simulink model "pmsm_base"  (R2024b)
settings: Solver=ode4  StartTime=0.0  StopTime=1  FixedStep=1e-6  RelTol=1e-3
undefined symbols (not defined in the file or in its folder): by, DiscIntNeverNeededParam, established, Flux, linkage, magnets, V
libraries: spsDCVoltageSourceLib x1, spsPermanentMagnetSynchronousMachineLib x1, simulink x1, spsTwoLevelConverterLib x1, sps_lib x1

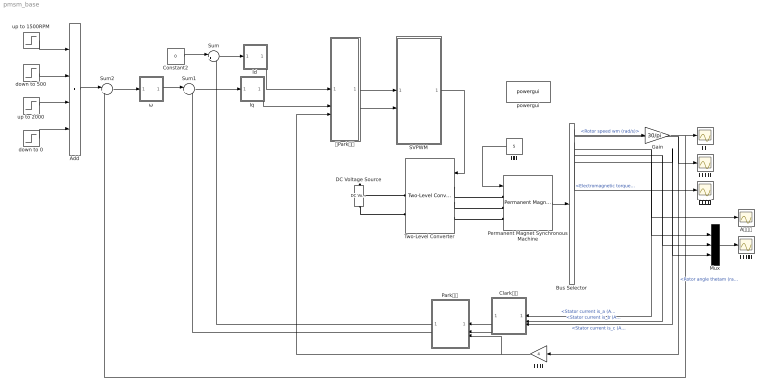
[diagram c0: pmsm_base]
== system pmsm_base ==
  Add : Sum  Inputs=++++
  A相电流 : Scope
  Bus Selector : BusSelector  OutputSignals=Rotor speed wm (rad/s),Rotor angle thetam (rad),Electromagnetic torque Te (N*m),Stator current is_a (A),Stator current is_b (A),Stator current is_c (A)
  Clark变换 : Subsystem
  Constant2 : Constant  Value=0
  DC Voltage Source : spsDCVoltageSourceLib/DC Voltage Source  Amplitude=560  Measurements=None
  Gain : Gain  Gain=30/pi
  Id : Subsystem  mask{Kp=9, Ki=800, Par_limits=[323 -323], Init=0, Ts=1e-6, Kb=89}
      mask prompts: Kp "Proportional gain(Kp):"; Ki "Integral gain(Ki):"; Par_limits "Output limits:[Upper Lower]"; Init "Output Init value:"; Ts "Sample time:"; Kb "Anti-windup gain Kb (1/s)"
      mask init:
      | Upperlimit = Par_limits(1);
      | Lowerlimit = Par_limits(2);
  Iq : Subsystem  mask{Kp=12, Ki=3000, Par_limits=[323 -323], Init=0, Ts=1e-6, Kb=250}
      mask prompts: Kp "Proportional gain(Kp):"; Ki "Integral gain(Ki):"; Par_limits "Output limits:[Upper Lower]"; Init "Output Init value:"; Ts "Sample time:"; Kb "Anti-windup gain Kb (1/s)"
      mask init:
      | Upperlimit = Par_limits(1);
      | Lowerlimit = Par_limits(2);
  Mux : Mux  Inputs=3
  Park变换 : Subsystem
  Permanent Magnet Synchronous Machine : spsPermanentMagnetSynchronousMachineLib/Permanent Magnet Synchronous Machine  NbPhases=3  FluxDistribution=Sinusoidal  RotorType=Round  MechanicalLoad=Torque Tm  PresetModel="11:  26.13 Nm 560 Vdc 3000 RPM - 27.3 Nm"  ShowDetailedParameters=on  MeasurementBus=off  Resistance=0.11  Inductance=8.5e-3  dqInductances=[8.5e-3,8.5e-3]  La=0.00097  MachineConstant=Flux linkage established by magnets (V.s)  Flux=0.1119  VoltageCst=81.1857  TorqueCst=0.6714  Flat=120  Mechanical=[0.0016 0.0002024 4 0]  PolePairs=4  InitialConditions=[0,0, 0,0]  InitialConditions5ph=[0 0 0 0 0 0]  RefAngle=Aligned with phase A axis (original Park)  IterativeDiscreteModel=Trapezoidal non iterative  TsBlock=-1  TsPowergui=0
  SVPWM : Subsystem
  Sum : Sum  Inputs=|+-
  Sum1 : Sum  Inputs=|+-
  Sum2 : Sum  Inputs=|+-
  Two-Level Converter : spsTwoLevelConverterLib/Two-Level Converter  ModelType=Switching devices  Ron=1e-3  Rs=1e6  Cs=inf  Vforward=[0,0]  Ron_Diode=1e-3  Rs_Diode=1e6  Cs_Diode=inf  Vf_Diode=1e-3  Rs_CurrentSource=inf  Ron_ACsource=1e-3
  down to 0 : Step  Time=0.8  After=-2000  SampleTime=0
  down to 500 : Step  Time=0.4  After=-1000  SampleTime=0
  powergui : sps_lib/powergui  Priority=1  SimulationMode=Discrete  SampleTime=1e-6  frequency=60  Iterations=50  frequencyindice=0  Pbase=100e6  ErrMax=1e-4  UnitsV=kV  UnitsW=MW  buscounter=0  FunctionMessages=off  echomessages=off  EnableUseOfTLC=off  CurrentSourceSwitches=off  DisableSnubberDevices=off  DisableRonSwitches=off  DisableVfSwitches=off  DisplayEquations=off  AutomaticDiscreteSolvers=off  SolverType=Tustin/Backward Euler (TBE)  Interpol=off  ExternalGateDelay=off  methode=off  Ts=100  x0status=blocks  SPID=on  SwTol=0  HookPort=off  NonlinearTolerance=1e-4  nMaxIteration=100  ContinueOnMaxIteration=off  RestoreLinks=warning  ResistiveCurrentMeasurement=off  Frange=[0:2:500]  Ylog=off  Xlog=on  ShowGrid=off  save=off  variable=ZData  structure=0  ZoomFFT=off  StartTime=0.0  cycles=1  DisplayStyle=1  fundamental=60  FreqAxis=off  MaxFrequency=1000  frequencyindicesteady=1  RmsSteady=1  display=off
  up to 1500RPM : Step  Time=0.1  After=1500  SampleTime=0
  up to 2000 : Step  Time=0.6  After=1500  SampleTime=0
  ω : Subsystem  mask{Kp=1.2, Ki=1000, Par_limits=[30 -30], Init=0, Ts=1e-6, Kb=1600}
      mask prompts: Kp "Proportional gain(Kp):"; Ki "Integral gain(Ki):"; Par_limits "Output limits:[Upper Lower]"; Init "Output Init value:"; Ts "Sample time:"; Kb "Anti-windup gain Kb (1/s)"
      mask init:
      | Upperlimit = Par_limits(1);
      | Lowerlimit = Par_limits(2);
  反Park变换 : Subsystem
  定子电流 : Scope
  机械角度 : Scope
  极对数 : Gain  Gain=4
  电磁转矩 : Scope
  负载 : Constant  Value=5
  转速 : Scope
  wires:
  Constant2/1 -> Sum/1
  极对数/1 -> Park变换/3(angle), 反Park变换/3(angle)
  Sum1/1 -> Iq/1(Err)
  Park变换/1(D) -> Sum/2
  ω/1(Out) -> Sum1/1
  Sum2/1 -> ω/1(Err)
  Bus Selector/5 -> Mux/2, Clark变换/2(b)  "<Stator current is_b (A)>"
  Bus Selector/6 -> Mux/3, Clark变换/3(c)  "<Stator current is_c (A)>"
  Bus Selector/4 -> A相电流/1, Clark变换/1(a), Mux/1  "<Stator current is_a (A)>"
  Gain/1 -> Sum2/2, 转速/1
  Bus Selector/1 -> Gain/1  "<Rotor speed wm (rad/s)>"
  Iq/1(Out) -> 反Park变换/2(Q)
  Park变换/2(Q) -> Sum1/2
  Bus Selector/3 -> 电磁转矩/1  "<Electromagnetic torque Te (N*m)>"
  Permanent Magnet Synchronous Machine/1 -> Bus Selector/1
  Bus Selector/2 -> 极对数/1, 机械角度/1  "<Rotor angle thetam (rad)>"
  SVPWM/1(PWM) -> Two-Level Converter/1
  反Park变换/1(alpha) -> SVPWM/1(alpha)
  反Park变换/2(beta) -> SVPWM/2(beta)
  Clark变换/1(alpha) -> Park变换/1(alpha)
  Clark变换/2(beta) -> Park变换/2(beta)
  Mux/1 -> 定子电流/1
  负载/1 -> Permanent Magnet Synchronous Machine/1
  Sum/1 -> Id/1(Err)
  Id/1(Out) -> 反Park变换/1(D)
  up to 2000/1 -> Add/3
  down to 0/1 -> Add/4
  down to 500/1 -> Add/2
  up to 1500RPM/1 -> Add/1
  Add/1 -> Sum2/1
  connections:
  DC Voltage Source/LConn1 -- Two-Level Converter/RConn2
  Two-Level Converter/LConn2 -- Permanent Magnet Synchronous Machine/LConn2
  DC Voltage Source/RConn1 -- Two-Level Converter/RConn1
  Two-Level Converter/LConn1 -- Permanent Magnet Synchronous Machine/LConn1
  Two-Level Converter/LConn3 -- Permanent Magnet Synchronous Machine/LConn3

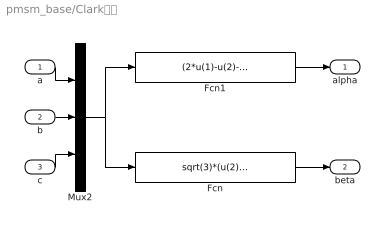
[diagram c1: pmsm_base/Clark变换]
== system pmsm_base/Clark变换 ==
  a : Inport
  b : Inport  Port=2
  c : Inport  Port=3
  Fcn : Fcn  Expr=sqrt(3)*(u(2)-u(3))/3
  Fcn1 : Fcn  Expr=(2*u(1)-u(2)-u(3))/3
  Mux2 : Mux  Inputs=3
  alpha : Outport
  beta : Outport  Port=2
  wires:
  Mux2/1 -> Fcn1/1, Fcn/1
  a/1 -> Mux2/1
  c/1 -> Mux2/3
  b/1 -> Mux2/2
  Fcn1/1 -> alpha/1
  Fcn/1 -> beta/1

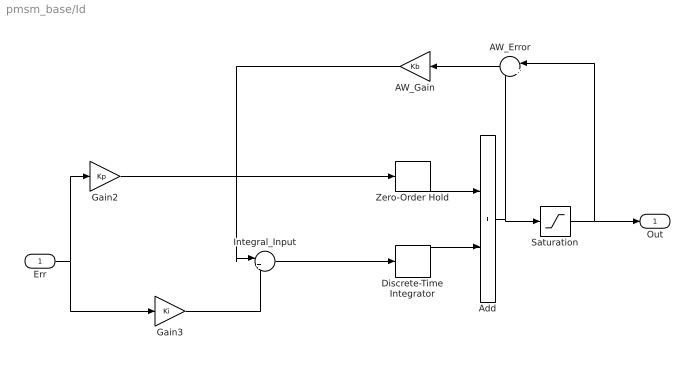
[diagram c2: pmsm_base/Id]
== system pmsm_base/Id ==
  Err : Inport
  AW_Error : Sum  Inputs=|+-
  AW_Gain : Gain  Gain=Kb
  Add : Sum
  Discrete-Time Integrator : DiscreteIntegrator  InitialCondition=Init  SampleTime=Ts  LimitOutput=on  UpperSaturationLimit=160  LowerSaturationLimit=-160  ICPrevOutput=DiscIntNeverNeededParam  ICPrevScaledInput=DiscIntNeverNeededParam
  Gain2 : Gain  Gain=Kp
  Gain3 : Gain  Gain=Ki
  Integral_Input : Sum  Inputs=|++
  Saturation : Saturate  UpperLimit=Upperlimit  LowerLimit=Lowerlimit
  Zero-Order Hold : ZeroOrderHold  SampleTime=Ts
  Out : Outport
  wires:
  Discrete-Time Integrator/1 -> Add/2
  Zero-Order Hold/1 -> Add/1
  Saturation/1 -> AW_Error/1, Out/1
  Add/1 -> AW_Error/2, Saturation/1
  Gain2/1 -> Zero-Order Hold/1
  Err/1 -> Gain2/1, Gain3/1
  AW_Error/1 -> AW_Gain/1
  AW_Gain/1 -> Integral_Input/1
  Gain3/1 -> Integral_Input/2
  Integral_Input/1 -> Discrete-Time Integrator/1

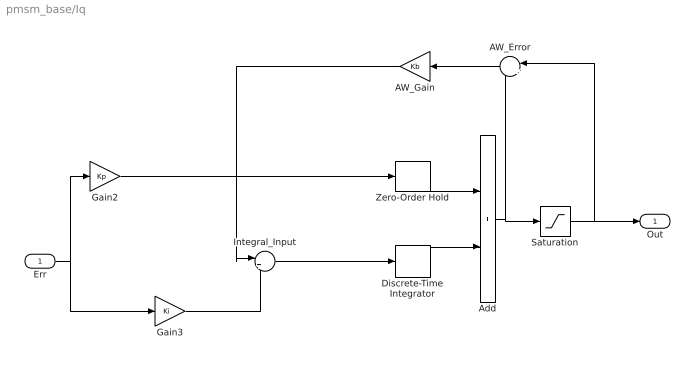
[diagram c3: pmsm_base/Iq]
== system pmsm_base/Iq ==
  Err : Inport
  AW_Error : Sum  Inputs=|+-
  AW_Gain : Gain  Gain=Kb
  Add : Sum
  Discrete-Time Integrator : DiscreteIntegrator  InitialCondition=Init  SampleTime=Ts  LimitOutput=on  UpperSaturationLimit=160  LowerSaturationLimit=-160  ICPrevOutput=DiscIntNeverNeededParam  ICPrevScaledInput=DiscIntNeverNeededParam
  Gain2 : Gain  Gain=Kp
  Gain3 : Gain  Gain=Ki
  Integral_Input : Sum  Inputs=|++
  Saturation : Saturate  UpperLimit=Upperlimit  LowerLimit=Lowerlimit
  Zero-Order Hold : ZeroOrderHold  SampleTime=Ts
  Out : Outport
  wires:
  Integral_Input/1 -> Discrete-Time Integrator/1
  Gain3/1 -> Integral_Input/2
  AW_Gain/1 -> Integral_Input/1
  AW_Error/1 -> AW_Gain/1
  Err/1 -> Gain3/1, Gain2/1
  Gain2/1 -> Zero-Order Hold/1
  Add/1 -> Saturation/1, AW_Error/2
  Saturation/1 -> Out/1, AW_Error/1
  Zero-Order Hold/1 -> Add/1
  Discrete-Time Integrator/1 -> Add/2

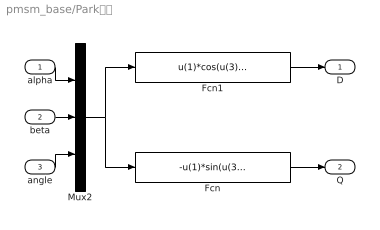
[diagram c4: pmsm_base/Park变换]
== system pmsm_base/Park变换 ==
  alpha : Inport
  beta : Inport  Port=2
  angle : Inport  Port=3
  Fcn : Fcn  Expr=-u(1)*sin(u(3))+u(2)*cos(u(3))
  Fcn1 : Fcn  Expr=u(1)*cos(u(3))+u(2)*sin(u(3))
  Mux2 : Mux  Inputs=3
  D : Outport
  Q : Outport  Port=2
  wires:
  Mux2/1 -> Fcn1/1, Fcn/1
  alpha/1 -> Mux2/1
  angle/1 -> Mux2/3
  beta/1 -> Mux2/2
  Fcn1/1 -> D/1
  Fcn/1 -> Q/1

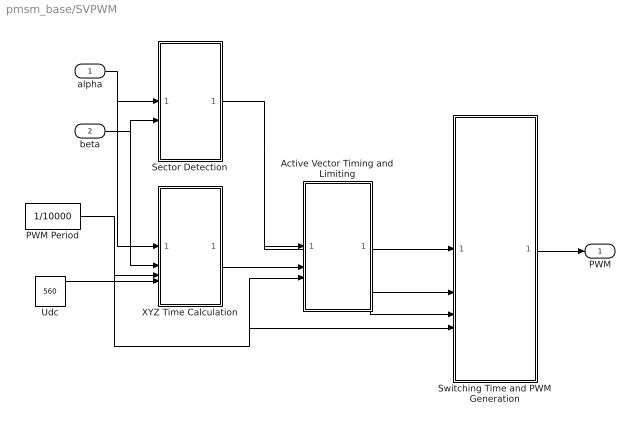
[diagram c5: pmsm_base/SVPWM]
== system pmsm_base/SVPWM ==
  alpha : Inport
  beta : Inport  Port=2
  Active Vector Timing and Limiting : Subsystem
  PWM Period : Constant  Value=1/10000
  Sector Detection : Subsystem
  Switching Time and PWM Generation : Subsystem
  Udc : Constant  Value=560
  XYZ Time Calculation : Subsystem
  PWM : Outport
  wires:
  alpha/1 -> XYZ Time Calculation/1(alpha), Sector Detection/1(alpha)
  beta/1 -> XYZ Time Calculation/2(beta), Sector Detection/2(beta)
  Sector Detection/1(N) -> Switching Time and PWM Generation/1(N), Active Vector Timing and Limiting/1(N)
  PWM Period/1 -> XYZ Time Calculation/3(Ts), Switching Time and PWM Generation/4(Ts), Active Vector Timing and Limiting/3(Ts)
  Active Vector Timing and Limiting/1(T1) -> Switching Time and PWM Generation/2(T1)
  Active Vector Timing and Limiting/2(T2) -> Switching Time and PWM Generation/3(T2)
  XYZ Time Calculation/1(XYZ) -> Active Vector Timing and Limiting/2(XYZ)
  Udc/1 -> XYZ Time Calculation/4(Udc)
  Switching Time and PWM Generation/1(PWM) -> PWM/1

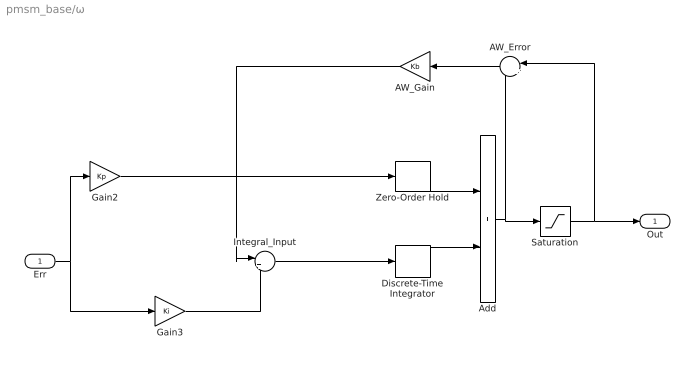
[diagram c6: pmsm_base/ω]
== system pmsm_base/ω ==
  Err : Inport
  AW_Error : Sum  Inputs=|+-
  AW_Gain : Gain  Gain=Kb
  Add : Sum
  Discrete-Time Integrator : DiscreteIntegrator  InitialCondition=Init  SampleTime=Ts  LimitOutput=on  UpperSaturationLimit=23  LowerSaturationLimit=-23  ICPrevOutput=DiscIntNeverNeededParam  ICPrevScaledInput=DiscIntNeverNeededParam
  Gain2 : Gain  Gain=Kp
  Gain3 : Gain  Gain=Ki
  Integral_Input : Sum  Inputs=|++
  Saturation : Saturate  UpperLimit=Upperlimit  LowerLimit=Lowerlimit
  Zero-Order Hold : ZeroOrderHold  SampleTime=Ts
  Out : Outport
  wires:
  Discrete-Time Integrator/1 -> Add/2
  Zero-Order Hold/1 -> Add/1
  Saturation/1 -> AW_Error/1, Out/1
  Add/1 -> AW_Error/2, Saturation/1
  Gain2/1 -> Zero-Order Hold/1
  Err/1 -> Gain2/1, Gain3/1
  AW_Error/1 -> AW_Gain/1
  AW_Gain/1 -> Integral_Input/1
  Gain3/1 -> Integral_Input/2
  Integral_Input/1 -> Discrete-Time Integrator/1

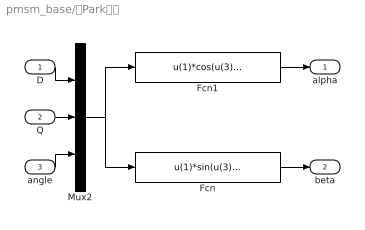
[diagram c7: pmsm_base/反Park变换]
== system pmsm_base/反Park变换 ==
  D : Inport
  Q : Inport  Port=2
  angle : Inport  Port=3
  Fcn : Fcn  Expr=u(1)*sin(u(3))+u(2)*cos(u(3))
  Fcn1 : Fcn  Expr=u(1)*cos(u(3))-u(2)*sin(u(3))
  Mux2 : Mux  Inputs=3
  alpha : Outport
  beta : Outport  Port=2
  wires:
  Mux2/1 -> Fcn1/1, Fcn/1
  D/1 -> Mux2/1
  angle/1 -> Mux2/3
  Q/1 -> Mux2/2
  Fcn1/1 -> alpha/1
  Fcn/1 -> beta/1

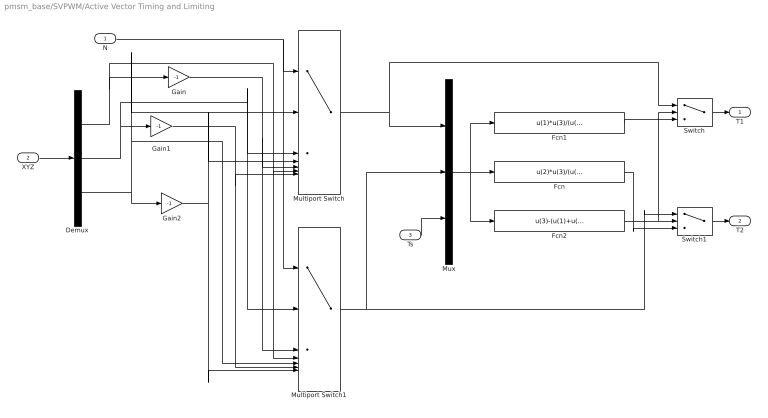
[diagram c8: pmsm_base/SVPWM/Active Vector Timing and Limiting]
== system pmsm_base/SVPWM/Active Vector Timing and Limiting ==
  N : Inport
  XYZ : Inport  Port=2
  Ts : Inport  Port=3
  Demux : Demux  Outputs=3
  Fcn : Fcn  Expr=u(2)*u(3)/(u(1)+u(2))
  Fcn1 : Fcn  Expr=u(1)*u(3)/(u(1)+u(2))
  Fcn2 : Fcn  Expr=u(3)-(u(1)+u(2))
  Gain : Gain  Gain=-1
  Gain1 : Gain  Gain=-1
  Gain2 : Gain  Gain=-1
  Multiport Switch : MultiPortSwitch  Inputs=6
  Multiport Switch1 : MultiPortSwitch  Inputs=6
  Mux : Mux  Inputs=3
  Switch : Switch  Criteria=u2 > Threshold
  Switch1 : Switch  Criteria=u2 > Threshold
  T1 : Outport
  T2 : Outport  Port=2
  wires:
  XYZ/1 -> Demux/1
  N/1 -> Multiport Switch/1, Multiport Switch1/1
  Demux/1 -> Multiport Switch/6, Multiport Switch1/4, Gain/1
  Gain/1 -> Multiport Switch1/3, Multiport Switch/5
  Demux/2 -> Multiport Switch/3, Multiport Switch1/2, Gain1/1
  Gain1/1 -> Multiport Switch1/6, Multiport Switch/7
  Demux/3 -> Multiport Switch1/5, Multiport Switch/2, Gain2/1
  Gain2/1 -> Multiport Switch1/7, Multiport Switch/4
  Multiport Switch/1 -> Mux/1, Switch/1
  Multiport Switch1/1 -> Mux/2, Switch1/1
  Ts/1 -> Mux/3
  Mux/1 -> Fcn/1, Fcn2/1, Fcn1/1
  Fcn2/1 -> Switch/2, Switch1/2
  Fcn1/1 -> Switch/3
  Fcn/1 -> Switch1/3
  Switch/1 -> T1/1
  Switch1/1 -> T2/1

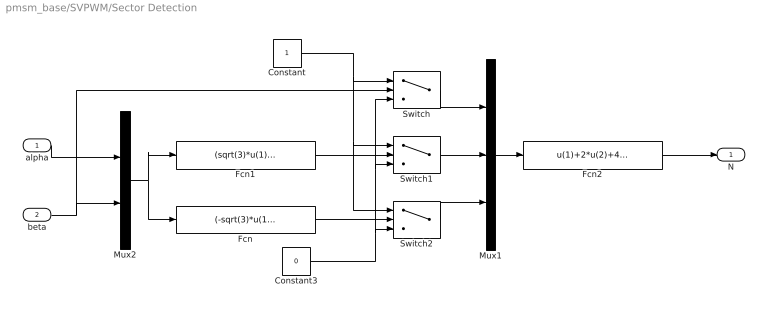
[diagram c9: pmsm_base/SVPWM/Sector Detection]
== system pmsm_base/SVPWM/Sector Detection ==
  alpha : Inport
  beta : Inport  Port=2
  Constant : Constant
  Constant3 : Constant  Value=0
  Fcn : Fcn  Expr=(-sqrt(3)*u(1)-u(2))/2
  Fcn1 : Fcn  Expr=(sqrt(3)*u(1)-u(2))/2
  Fcn2 : Fcn  Expr=u(1)+2*u(2)+4*u(3)
  Mux1 : Mux  Inputs=3
  Mux2 : Mux  Inputs=2
  Switch : Switch  Criteria=u2 > Threshold
  Switch1 : Switch  Criteria=u2 > Threshold
  Switch2 : Switch  Criteria=u2 > Threshold
  N : Outport
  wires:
  Constant3/1 -> Switch/3, Switch1/3, Switch2/3
  Switch/1 -> Mux1/1
  Mux2/1 -> Fcn/1, Fcn1/1
  Mux1/1 -> Fcn2/1
  Fcn1/1 -> Switch1/2
  Constant/1 -> Switch/1, Switch1/1, Switch2/1
  Switch2/1 -> Mux1/3
  Fcn/1 -> Switch2/2
  Switch1/1 -> Mux1/2
  beta/1 -> Switch/2, Mux2/2
  alpha/1 -> Mux2/1
  Fcn2/1 -> N/1

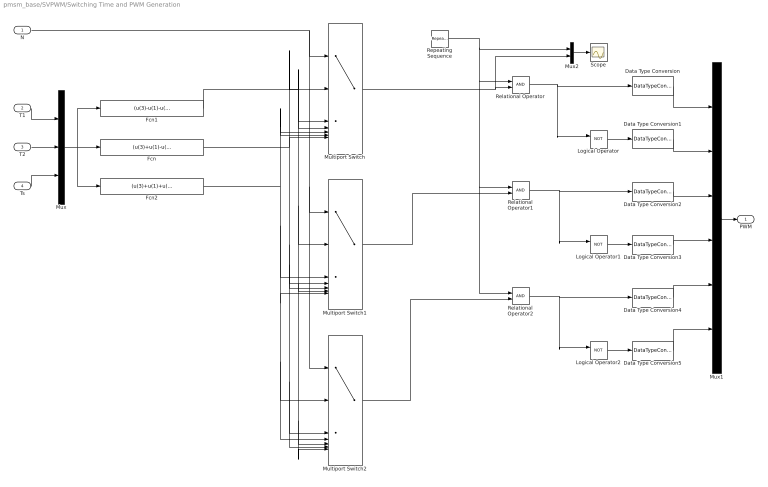
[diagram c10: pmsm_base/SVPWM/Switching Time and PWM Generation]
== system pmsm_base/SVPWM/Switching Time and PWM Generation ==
  N : Inport
  T1 : Inport  Port=2
  T2 : Inport  Port=3
  Ts : Inport  Port=4
  Data Type Conversion{,1..5} (6 alike) : DataTypeConversion  OutDataTypeStr=double
  Fcn : Fcn  Expr=(u(3)+u(1)-u(2))/4
  Fcn1 : Fcn  Expr=(u(3)-u(1)-u(2))/4
  Fcn2 : Fcn  Expr=(u(3)+u(1)+u(2))/4
  Logical Operator : Logic  Operator=NOT  AllPortsSameDT=off  OutDataTypeStr=boolean
  Logical Operator1 : Logic  Operator=NOT  AllPortsSameDT=off  OutDataTypeStr=boolean
  Logical Operator2 : Logic  Operator=NOT  AllPortsSameDT=off  OutDataTypeStr=boolean
  Multiport Switch : MultiPortSwitch  Inputs=6
  Multiport Switch1 : MultiPortSwitch  Inputs=6
  Multiport Switch2 : MultiPortSwitch  Inputs=6
  Mux : Mux  Inputs=3
  Mux1 : Mux  Inputs=6
  Mux2 : Mux  Inputs=2
  Relational Operator : RelationalOperator  OutDataTypeStr=boolean  RndMeth=Simplest
  Relational Operator1 : RelationalOperator  OutDataTypeStr=boolean  RndMeth=Simplest
  Relational Operator2 : RelationalOperator  OutDataTypeStr=boolean  RndMeth=Simplest
  Repeating Sequence : simulink/Sources/Repeating Sequence  rep_seq_t=[0 1/20000 1/10000]  rep_seq_y=[0 1/20000 0]
  Scope : Scope
  PWM : Outport
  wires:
  T2/1 -> Mux/2
  T1/1 -> Mux/1
  Ts/1 -> Mux/3
  N/1 -> Multiport Switch1/1, Multiport Switch2/1, Multiport Switch/1
  Mux/1 -> Fcn/1, Fcn2/1, Fcn1/1
  Fcn1/1 -> Multiport Switch1/2, Multiport Switch1/6, Multiport Switch2/5, Multiport Switch2/7, Multiport Switch/3, Multiport Switch/4
  Fcn/1 -> Multiport Switch2/6, Multiport Switch2/3, Multiport Switch1/5, Multiport Switch1/4, Multiport Switch/7, Multiport Switch/2
  Fcn2/1 -> Multiport Switch2/4, Multiport Switch2/2, Multiport Switch1/7, Multiport Switch1/3, Multiport Switch/5, Multiport Switch/6
  Mux1/1 -> PWM/1
  Relational Operator/1 -> Logical Operator/1, Data Type Conversion/1
  Logical Operator/1 -> Data Type Conversion1/1
  Logical Operator1/1 -> Data Type Conversion3/1
  Logical Operator2/1 -> Data Type Conversion5/1
  Relational Operator1/1 -> Logical Operator1/1, Data Type Conversion2/1
  Relational Operator2/1 -> Logical Operator2/1, Data Type Conversion4/1
  Multiport Switch/1 -> Mux2/2, Relational Operator/2
  Multiport Switch1/1 -> Relational Operator1/2
  Multiport Switch2/1 -> Relational Operator2/2
  Data Type Conversion/1 -> Mux1/1
  Data Type Conversion1/1 -> Mux1/2
  Data Type Conversion2/1 -> Mux1/3
  Data Type Conversion3/1 -> Mux1/4
  Data Type Conversion4/1 -> Mux1/5
  Data Type Conversion5/1 -> Mux1/6
  Mux2/1 -> Scope/1
  Repeating Sequence/1 -> Mux2/1, Relational Operator2/1, Relational Operator1/1, Relational Operator/1

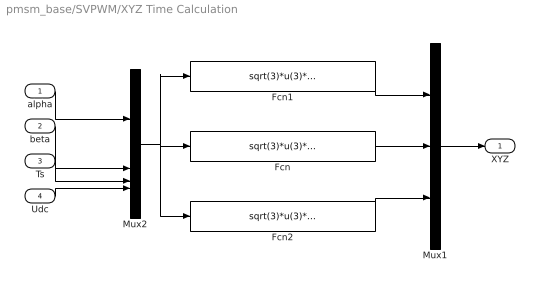
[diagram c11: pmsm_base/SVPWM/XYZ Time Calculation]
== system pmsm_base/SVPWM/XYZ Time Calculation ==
  alpha : Inport
  beta : Inport  Port=2
  Ts : Inport  Port=3
  Udc : Inport  Port=4
  Fcn : Fcn  Expr=sqrt(3)*u(3)*(sqrt(3)*u(1)+u(2))/(2*u(4))
  Fcn1 : Fcn  Expr=sqrt(3)*u(3)*u(2)/u(4)
  Fcn2 : Fcn  Expr=sqrt(3)*u(3)*(-sqrt(3)*u(1)+u(2))/(2*u(4))
  Mux1 : Mux  Inputs=3
  Mux2 : Mux
  XYZ : Outport
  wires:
  Mux2/1 -> Fcn2/1, Fcn1/1, Fcn/1
  beta/1 -> Mux2/2
  alpha/1 -> Mux2/1
  Ts/1 -> Mux2/3
  Udc/1 -> Mux2/4
  Mux1/1 -> XYZ/1
  Fcn/1 -> Mux1/2
  Fcn1/1 -> Mux1/1
  Fcn2/1 -> Mux1/3
